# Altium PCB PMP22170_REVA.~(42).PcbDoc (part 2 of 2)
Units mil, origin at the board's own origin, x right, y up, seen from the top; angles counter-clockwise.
Board outline 4950 x 3450 mil, 2 copper layers (Top Layer, Bottom Layer), stack 62 mil thick; 76 components, 28 nets, 168 pads, 70 vias.
Unrouted connection lines stored in the file: 126.

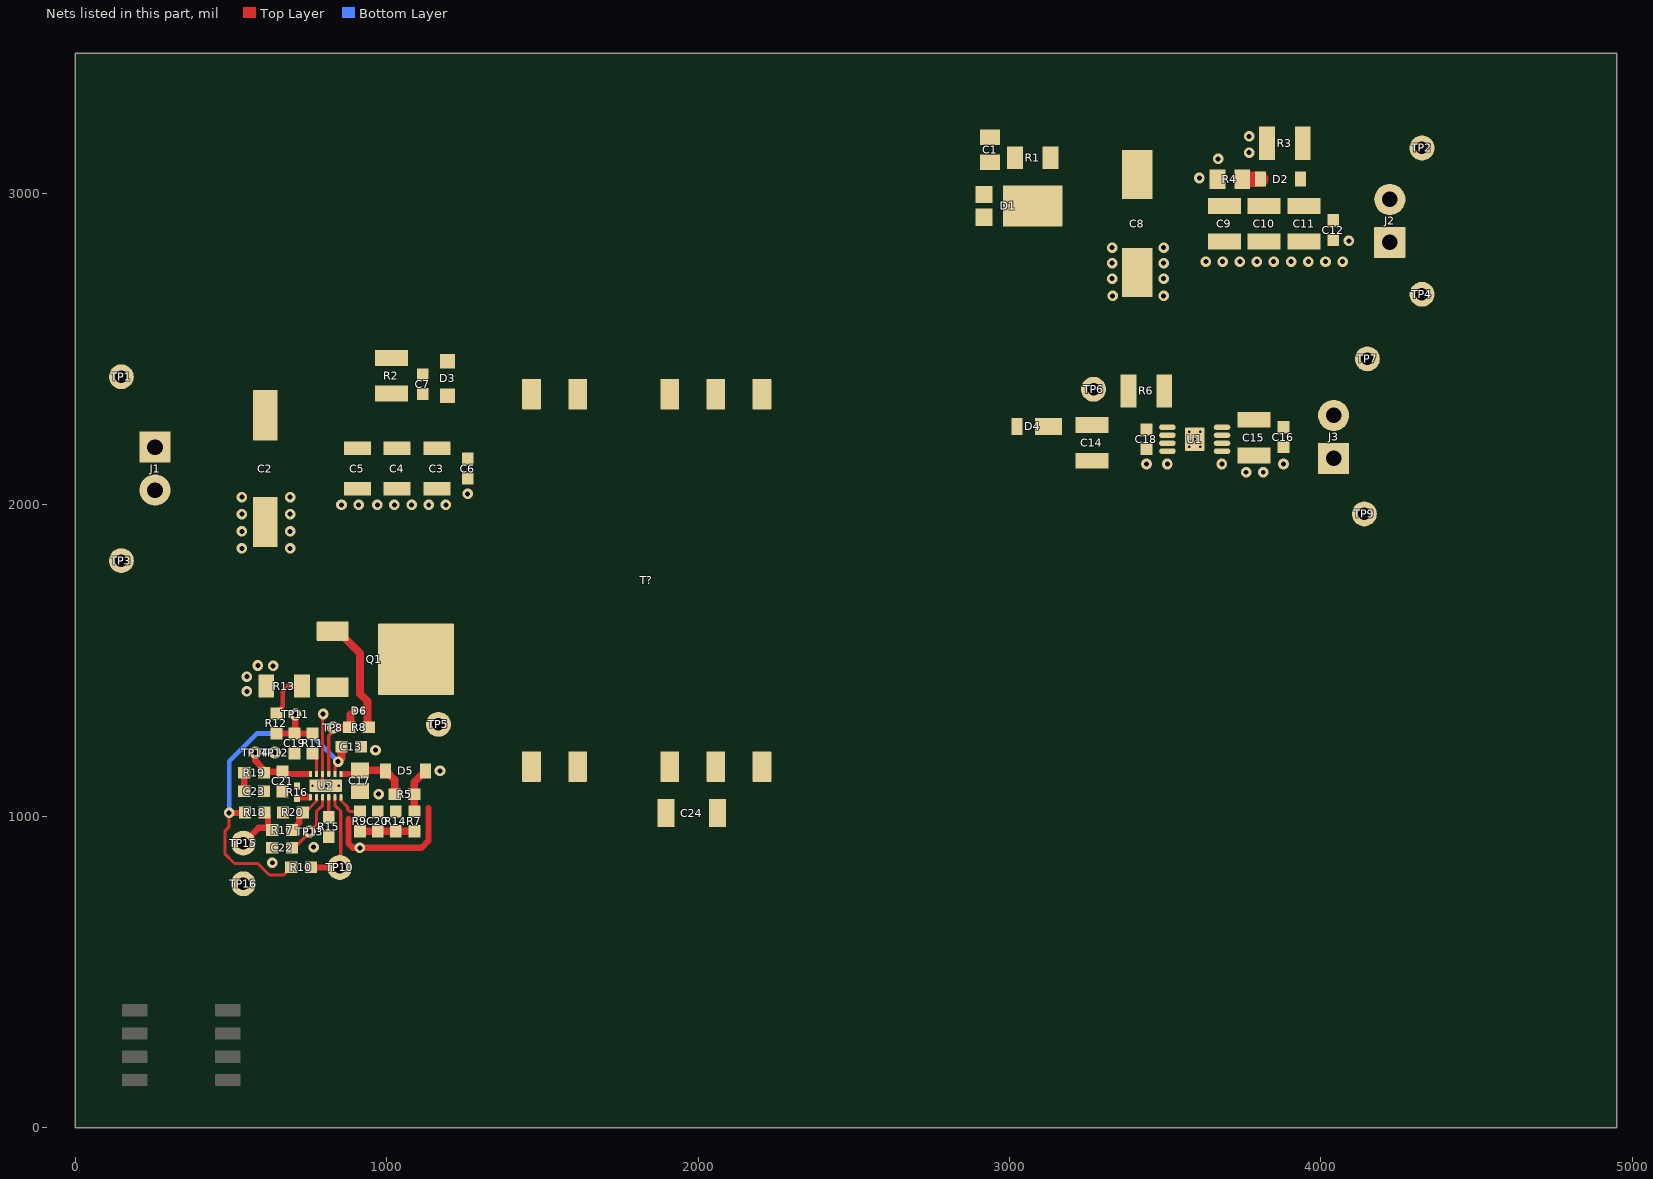
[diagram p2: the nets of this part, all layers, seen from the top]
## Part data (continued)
TP5: library part CMP-0055139-1, "Test Point, Miniature, White, TH", Color=White, Manufacturer=Keystone, Supplier Part Number 1=36-5002-ND
TP8 TP11 TP12 TP13 TP14: library part CMP-0003825-1, "1mm Test Point, SMT", Manufacturer=Any
TP15: library part CMP-0055140-1, "Test Point, Miniature, Orange, TH", Color=Orange, Manufacturer=Keystone, Supplier Part Number 1=36-5003-ND
U1: library part CMP-0013313-4, "300mA High-Voltage Ultra-Low-Iq Low-Dropout (LDO) Regulator, DGN0008D (VSSOP-8)", Alternate Manufacturer="Texas Instruments"
U2: library part CMP-0081538-1, "Automotive Grade 2.2-MHz Wide Input Non-synchronous Boost Controller, DSS0012C (WSON-12)", Alternate Manufacturer="Texas Instruments", Alternate PartNumber=LM5155QDSSRQ1

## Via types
v1: diameter 34, hole 16, Top Layer to Bottom Layer, 62 vias
v2: diameter 19.68, hole 7.87, Top Layer to Bottom Layer, 8 vias

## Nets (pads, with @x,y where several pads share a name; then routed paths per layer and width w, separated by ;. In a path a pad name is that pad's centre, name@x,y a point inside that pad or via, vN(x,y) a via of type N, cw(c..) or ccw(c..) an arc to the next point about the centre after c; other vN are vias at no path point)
GND: C2.1 C3.2 C4.2 C5.2 C6.2 C13.2 C14.2 C15.2 C16.2 C17.2 C18.2 C19.2 C20.2 C21.2 C22.2 C23.2 C24.2 J1.2 J3.1 R6.1 R13.1 R14.1 R15.1 R16.1 R20.1 T?.9 TP3.1 TP9.1 TP12.1 TP16.1 U1.3 U1.4 U1.5 U1.6 U1.7 U1.9 U2.4 U2.13@804.02,1098.17 | length 690.3
  Top Layer w10: v1(795.98,1328.19) 793.27,1325.47 793.27,1136.48 U2.4@794.17,1135.57 794.17,1108.01 v2(804.02,1098.17)
  Top Layer w20: 877.44,990.57 877.44,912.17 890.96,898.65 v1(914.02,898.65) 1112.09,898.65 1134.02,920.57 1134.02,1025.57
  other v1: 632.64,850.57 765.51,900.57 974.02,1070.57 640.98,1204.49 964.02,1212.31 550.98,1401.17 550.98,1448.19 635.04,1483.19 585.98,1484.09 535,1860 690,1860 535,1915 690,1915 535,1970 690,1970 854.76,1999.87 909.76,1999.87 969.76,1999.87 1024.76,1999.87 1080,1999.87 1135,1999.87 1189.76,1999.87 535,2025 690,2025 1260,2035 3760,2104.65 3815,2104.65 3440,2131.22 3506.93,2131.22 3682.11,2131.22 3880,2131.22
  other v2: 761.69,1098.17 846.34,1098.17 3577.28,2187.17 3612.72,2187.17 3595,2210.79 3577.28,2234.41 3612.72,2234.41
GND2: C8.2 C9.2 C10.2 C11.2 C12.2 C24.1 J2.1 R3.1 R4.1 T?.7 T?.8 TP4.1
  other v1: 3331.22,2671.22 3495,2671.22 3330,2726.22 3495,2726.22 3330,2776.22 3495,2776.22 3630.94,2781.22 3684.76,2781.22 3739.76,2781.22 3794.76,2781.22 3848.19,2781.22 3904.76,2781.22 3959.76,2781.22 4015,2781.22 4070,2781.22 3330,2826.22 3495,2826.22 4090,2847.81 3610,3049.58 3670.31,3111.22 3769.76,3131.22 3769.76,3183.7
NetC1_1: C1.1 R1.1
NetC1_2: C1.2 D1.1 D1.2 T?.5 T?.6
NetC2_2: C2.2 C3.1 C4.1 C5.1 C6.1 C7.1 D5.2 J1.1 R2.2 R5.2 R7.2 T?.11 T?.12 TP1.1 | length 145.7
  Top Layer w25: R7.2@1089.06,1015.02 1088.7,1015.38 R5.2@1088.7,1070.57 1088.7,1109.29 D5.2@1124.98,1145.57
  other v1: 1170.98,1145.57
NetC7_2: C7.2 D3.1 R2.1
NetC8_1: C8.1 C9.1 C10.1 C11.1 C12.1 D1.3 D2.1 J2.2 R1.2 R3.2 TP2.1
NetC13_1: C13.1 C14.1 C18.1 D4.1 R6.2 R10.1 R18.2 TP6.1 U1.1 U1.2 U2.2 | length 1125.5
  Top Layer w10: v1(494.02,1010.57) 494.02,966.37 480.98,953.34 480.98,878.19 510.98,848.19 585.98,848.19 622.93,811.24 669.33,811.24 R10.1@693.66,835.57 ; U2.2@833.54,1135.57 833.54,1155.63 844.02,1166.1 v1(844.02,1175.57)
  Top Layer w20: v1(494.02,1010.57) 542.97,1010.57 R18.2@544.47,1012.07
  Top Layer w25: v1(844.02,1175.57) 854.49,1186.05 C13.1@854.49,1223.19
  Bottom Layer w15: v1(494.02,1010.57) 494.02,1176.22 583.25,1265.45 754.13,1265.45 v1(844.02,1175.57)
NetC15_1: C15.1 C16.1 J3.2 TP7.1 U1.8
NetC17_1: C17.1 D5.1 R5.1 U2.1 | length 235.8
  Top Layer w10: U2.1@853.23,1135.57 859.02,1135.57
  Top Layer w20: 859.02,1135.57 902.13,1135.57 C17.1@914.06,1147.5
  Top Layer w25: C17.1@914.06,1147.5 994.11,1147.5 D5.1@996.04,1145.57 1025.71,1115.91 R5.1@1025.71,1070.57
NetC19_1: C19.1 R11.2 R12.1 TP11.1 | length 178.8
  Top Layer w20: R12.1@645.98,1266.69 647.22,1265.45 C19.1@704.02,1265.45 ; v1(706.46,1327.03) 706.46,1267.9 C19.1@704.02,1265.45 ; R11.2@761.69,1265.45 C19.1@704.02,1265.45
NetC20_1: C20.1 R7.1 R9.1 R14.2 | length 175
  Top Layer w25: R9.1@914.02,952.03 C20.1@971.02,952.03 R7.1@1089.06,952.03
NetC21_1: C21.1 R19.2 TP14.1 U2.6 | length 231
  Top Layer w10: 746.93,1135.57 U2.6@754.8,1135.57
  Top Layer w20: v1(577.66,1204.49) 577.66,1178.98 605.51,1151.12 R19.2@605.51,1139.08 609.51,1143.07 C21.1@665.51,1143.07 673.01,1135.57 746.93,1135.57
NetC22_1: C22.1 TP13.1 U2.9 | length 207.4
  Top Layer w10: C22.1@695.63,898.65 703.23,898.65 752.72,948.13 v1(752.72,950.57) 774.49,972.34 774.49,1015.77 794.17,1035.46 U2.9@794.17,1060.77
NetC23_1: C23.1 R19.1 | length 58.5
  Top Layer w20: C23.1@542.52,1080.57 R19.1@542.52,1139.08
NetD2_2: D2.2 R4.2 | length 57.9
  Top Layer w50: R4.2@3748.19,3046.22 D2.2@3806.12,3046.22
NetD3_2: D3.2 Q1.2 T?.1 T?.2 TP5.1
NetD4_2: D4.2 T?.4
NetD6_1: D6.1 R8.2 TP8.1 U2.3 | length 265.8
  Top Layer w10: U2.3@813.86,1135.57 813.86,1258.33 827.44,1271.91 v1(827.44,1284.71)
  Top Layer w15: 883.43,1327.03 D6.1@896.08,1336.39
  Top Layer w25: v1(827.44,1284.71) 878.33,1284.71 R8.2@879.49,1285.87 883.43,1289.81 883.43,1327.03
NetD6_2: D6.2 Q1.1 R8.1 | length 366
  Top Layer w25: Q1.1@826.38,1593.86 843.35,1593.86 914.06,1523.15 914.06,1393.47 938.54,1368.98 938.54,1289.81 R8.1@942.48,1285.87
NetQ1_3: Q1.3 R12.2 R13.2 | length 148.1
  Top Layer w15: R12.2@645.98,1329.69 655.98,1339.69 655.98,1342.09 665.98,1352.09 665.98,1401.17 683.01,1418.19 R13.2@727.26,1418.19
NetR9_2: R9.2 U2.12 | length 90.3
  Top Layer w10: U2.12@853.23,1060.77 853.23,1050.59 874.69,1029.14 874.69,1021.24 880.91,1015.02 R9.2@914.02,1015.02
NetR11_1: R11.1 U2.5 | length 72.2
  Top Layer w10: R11.1@761.69,1202.46 774.49,1189.67 U2.5@774.49,1135.57
NetR15_2: R15.2 U2.10 | length 63.7
  Top Layer w10: R15.2@813.86,997.07 U2.10@813.86,1060.77
NetR16_2: R16.2 U2.7 | length 43.8
  Top Layer w10: 746.94,1060.77 U2.7@754.8,1060.77
  Top Layer w20: R16.2@712.36,1057.44 715.69,1060.77 746.94,1060.77
NetR17_1: R17.1 R18.1 TP15.1 | length 169.3
  Top Layer w20: TP15.1@539.57,913.64 588.57,962.64 612.58,962.64 R17.1@619.02,969.08 ; R18.1@607.46,1012.07 619.02,1000.51 R17.1@619.02,969.08 ; R17.1@632.52,955.57 R17.1@619.02,969.08
NetR17_2: R17.2 R20.2 U2.8 | length 142.5
  Top Layer w10: R20.2@730.08,1012.07 737.92,1012.07 774.49,1048.64 U2.8@774.49,1060.77
  Top Layer w20: R17.2@695.51,955.57 719.02,979.08 719.02,1001.01 R20.2@730.08,1012.07
PG: R10.2 TP10.1 U2.11 | length 326.8
  Top Layer w10: U2.11@833.54,1060.77 833.54,1035.46 852.48,1016.52 852.48,839.04 TP10.1@849.02,835.57
  Top Layer w20: R10.2@756.65,835.57 TP10.1@849.02,835.57
pads on no net: T1.1 T1.2 T1.3 T1.4 T1.5 T1.6 T1.7 T1.8 U2.13@777.05,1098.17 U2.13@830.98,1098.17

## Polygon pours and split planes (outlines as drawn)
NetC2_2 on Top Layer "TOP_LAYER_NETC2_2_P016" (solid, remove dead copper, pour order 16): 70,2330
NetC2_2 on Top Layer "TOP_LAYER_NETC2_2_P014" (solid, remove dead copper, pour order 14): 130,2116.35 1278.52,2116.35 1278.54,2116.37 1278.54,2221.46 1250,2250 900,2250 689.54,2460.46 135.46,2460.46 100,2425 100,2145
NetQ1_3 on Top Layer "TOP_LAYER_NETQ1_3_P012" (solid, remove dead copper, pour order 12): 877.44,1461.73 870.98,1468.19 705.98,1468.19 700.98,1463.19 700.98,1374.17 706.46,1368.7 706.46,1368.19 868.65,1368.19 877.44,1376.98
NetQ1_3 on Top Layer "TOP_LAYER_NETQ1_3_P010" (solid, remove dead copper, pour order 10): 826.38,1414.33
NetC15_1 on Top Layer "TOP_LAYER_NETC15_1_P008" (solid, remove dead copper, pour order 8): 3654.04,2243.08 3654.04,2291.22 3724.04,2361.22 4149.45,2361.22 4149.45,2241.44 4126.18,2218.17 3749.9,2218.17 3731.85,2236.22 3731.54,2235.91 3661.22,2235.91
NetC13_1 on Top Layer "TOP_LAYER_NETC13_1_P006" (solid, remove dead copper, pour order 6): 3400,2251.22
NetC13_1 on Top Layer "TOP_LAYER_NETC13_1_P004" (solid, remove dead copper, pour order 4): 3420,2218.46 3536.04,2218.46 3536.04,2267.26 3527.09,2276.22 3420,2276.22
NetC8_1 on Top Layer "TOP_LAYER_NETC8_1_P002" (solid, remove dead copper, pour order 2): 3360,3141.22 3360,2891.22 4335.31,2891.22 4365,2920.91 4365,3165.83 4316.46,3214.37 3915,3214.37 3915,3111.22 3860,3056.22 3860,3008.62 3846.1,2994.72 3611.5,2994.72 3465,3141.22

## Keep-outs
Keep-Out Layer:
  text ".Layer_Name" at 577,-858.49 h60

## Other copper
Top Layer:
  text ".Layer_Name" at 577,-858.49 h60
Bottom Layer:
  text ".Layer_Name" at 577,-858.49 h60

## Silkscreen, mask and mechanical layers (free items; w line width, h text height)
Top Overlay:
  text "'.PRJ_Number'.PCB_Rev" at 3503.94,187.01 h108.27
  text ".Layer_Name" at 577,-858.49 h60
Bottom Overlay:
  text ".Layer_Name" at 577,-858.49 h60
Top Paste:
  text ".Layer_Name" at 577,-858.49 h60
Bottom Paste:
  text ".Layer_Name" at 577,-858.49 h60
Top Solder:
  text ".Layer_Name" at 577,-858.49 h60
  text ".Layer_Name" at 577,-858.49 h60
Bottom Solder:
  text ".Layer_Name" at 577,-858.49 h60
Drill Guide:
  text ".Layer_Name" at 577,-858.49 h60
M1 Board Outline:
  the board outline again, w10
  text ".Layer_Name" at 577,-858.49 h60
M2 Board Dimensions:
  rectangle: 0,-275 125,-150
  rectangle: 125,-400 500,-275
  lines w7: 0,-275 1000,-275 ; 125,-400 125,-150 ; 250,-400 250,-150 ; 500,-400 500,-150 ; 750,-400 750,-150 ; 0,-400 1000,-400 1000,-150 0,-150 0,-400
  text ".Layer_Name" at 577,-858.49 h60
M3 3D STEP Top:
  text ".Layer_Name" at 577,-858.49 h60
M4 3D STEP Bottom:
  text ".Layer_Name" at 577,-858.49 h60
M5 Assembly Top:
  lines w10: -292,-930.17 6308,-930.17 ; -292,-726.83 6310,-726.83 ; -292,-523.5 -292,-1133.5 3713,-1133.5 6310,-1133.5 6310,-523.5 -291.5,-523.5 -291.5,-1133.5 1284,-1133.5 ; 2173,-1133.5 2173,-523.5 ; 3440,-726.83 3440,-523.5 ; 4280,-726.83 4280,-523.5 ; 4902,-1140 4902,-937.17
  text "COMPONENTS MARKED 'DNP' SHOULD NOT BE POPULATED." at 1153.5,-318.5 h60
  text "ASSEMBLY VARIANT:" at 1153,-434 h60
  text ".VariantName" at 2189,-434 h60
  text "PCB VIEWED FROM TOP SIDE" at -228.5,-655.67 h60
  text "BOARD #:" at 2248,-655.67 h60
  text ".PRJ_Number" at 2793.5,-655.67 h60
  text "REV:" at 3638,-655.67 h60
  text ".PCB_Rev" at 3929.5,-655.67 h60
  text "SVN REV:" at 4476,-655.67 h60
  text ".VersionControl_RevNumber" at 4982,-655.67 h60
  text "TID #:" at 2248,-859 h60
  text ".TID" at 2793.5,-859 h60
  text "PLOT NAME =" at -228.5,-1064.34 h60
  text ".plot_File_Name" at 577,-1064.34 h60
  text "GENERATED    :" at 2250,-1064.34 h60
  text ".Print_Date" at 3119.5,-1064.34 h60
  text ".Print_Time" at 3848.5,-1064.34 h60
  text "TEXAS INSTRUMENTS" at 5113,-1064.34 h60
M6 Assembly Bottom:
  lines w10: -292.5,-727.33 6309.5,-727.33 ; -290.5,-930.67 6309.5,-930.67 ; 1115.5,-1140.5 1115.5,-937.67 ; 1737.5,-727.33 1737.5,-524 ; 2577.5,-727.33 2577.5,-524 ; 3844.5,-1134 3844.5,-524 ; 4733.5,-1134 6309,-1134 6309,-524 -292.5,-524 -292.5,-1134 2304.5,-1134 6309.5,-1134 6309.5,-524
  text "COMPONENTS MARKED 'DNP' SHOULD NOT BE POPULATED." at 6102,-318 h60
  text ".VariantName" at 5058,-434 h60
  text "ASSEMBLY VARIANT:" at 6097,-434 h60
  text ".VersionControl_RevNumber" at 1035.5,-656.17 h60
  text "SVN REV:" at 1541.5,-656.17 h60
  text ".PCB_Rev" at 2088,-656.17 h60
  text "REV:" at 2379.5,-656.17 h60
  text ".PRJ_Number" at 3224,-656.17 h60
  text "BOARD #:" at 3769.5,-656.17 h60
  text "PCB VIEWED FROM BOTTOM SIDE" at 6246,-656.17 h60
  text ".TID" at 3224,-859.5 h60
  text "TID #:" at 3769.5,-859.5 h60
  text "TEXAS INSTRUMENTS" at 904.5,-1064.84 h60
  text ".Print_Time" at 2169,-1064.84 h60
  text ".Print_Date" at 2898,-1064.84 h60
  text "GENERATED    :" at 3767.5,-1064.84 h60
  text ".plot_File_Name" at 5440.5,-1064.84 h60
  text "PLOT NAME =" at 6246,-1064.84 h60
M9 Title Sheet:
  drawing of 57 lines, arcs and shapes, not listed
  text "1" at 739.84,8036.5 h70
  text "2" at 3235.5,8036.5 h70
  text "3" at 5724.84,8036.5 h70
  text "4" at 8231.51,8036.5 h70
  text "5" at 10730.5,8036.5 h70
  text "6" at 13235.5,8036.5 h70
  text "A" at -416.5,6893.5 h70
  text "A" at 14383.5,6893.5 h70
  text "B" at -416.5,4513.5 h70
  text "B" at 14383.5,4513.5 h70
  text "C" at -416.5,2138.5 h70
  text "C" at 14383.5,2138.5 h70
  text "PROJECT TITLE:" at 11343.5,277.5 h45
  text ".PRJ_Title" at 11393.5,144.17 h70
  text "DESIGNED FOR:" at 11343.5,-23.5 h45
  text ".PRJ_Customer" at 11393.5,-163.5 h70
  text "D" at -416.5,-231.5 h70
  text "D" at 14383.5,-231.5 h70
  text "FILE NAME:" at 11343.5,-323.5 h45
  text ".PCB_File_Name_No_Path" at 11393.5,-443.5 h70
  text "Texas Instruments (TI) and/or its licensors do not warrant the accuracy or completeness of this specification" at 6374,-605.34 h45
  text "ENGINEER:" at 11343.5,-613.5 h45
  text "LAYOUT BY:" at 12848.5,-613.5 h45
  text "or any information contained therein. TI and/or its licensors do not warrant that this design will meet" at 6329.01,-718 h45
  text ".PRJ_Engineer" at 11393.5,-768.49 h70
  text ".PCB_Layout" at 12899,-768.49 h70
  text "the specifications, will be suitable for your application or fit for any particular purpose, or will operate in" at 6329.01,-830.67 h45
  text ".Layer_Name" at 577,-858.49 h60
  text "ALTIUM DESIGNER VERSION:" at 12848.5,-923.5 h45
  text "an implementation. TI and/or its licensors do not warrant that the design is production worthy. You should" at 6329.01,-943.33 h45
  text "completely validate and test your design implementation to confirm the system functionality for your application." at 6374,-1056 h45
  text ".print_Scale" at 11393.5,-1056.83 h70
  text ".Application_BuildNumber" at 12899,-1056.83 h70
  text "1" at 739.84,-1263.5 h70
  text "2" at 3235.5,-1263.5 h70
  text "3" at 5724.84,-1263.5 h70
  text "4" at 8231.51,-1263.5 h70
  text "5" at 10730.5,-1263.5 h70
  text "6" at 13235.5,-1263.5 h70
M10 Fab Notes:
  drawing of 189 lines, arcs and shapes, not listed
  text "DESIGN INFORMATION" at 12382.02,6356.17 h60
  text "MIN. TRACK WIDTH:" at 11737.46,6224.05 h60
  text "8" at 12833.7,6224.05 h60
  text "MIL" at 12988.46,6224.05 h60
  text "MIN. CLEARANCE:" at 11737.46,6099.92 h60
  text "0.2" at 12773.7,6099.93 h60
  text "mm" at 12988.46,6099.92 h60
  text "MIN. VIA PAD SIZE:" at 11737.46,5975.8 h60
  text "24" at 12803.71,5975.8 h60
  text "MIL" at 12988.46,5975.8 h60
  text "0.05mm (2MIL)" at 12432.46,5845.9 h60
  text "MINIMUM ANNULAR RING" at 11408.23,5837.67 h60
  text "EXTERNAL" at 13140.46,5837.67 h60
  text "PER" at 11608.23,5727.55 h60
  text "IPC-D-275 CLASS 2 LEVEL C" at 11828.23,5727.54 h60
  text "MIL, HOLES" at 13316.46,5627.07 h60
  text "+/-" at 12924,5618.48 h60
  text "+/-" at 13778,5618.48 h60
  text "REGISTRATION TOLERANCES:" at 11408.23,5617.42 h60
  text "METAL" at 12608,5617.42 h60
  text "5" at 13184.2,5617.42 h60
  text "3" at 14017.2,5617.42 h60
  text "MIL" at 14133.46,5617.42 h60
  text "HOLE SIZE TOLERANCE (UNLESS OTHERWISE SPECIFIED):" at 11408.23,5519.1 h60
  text "+/-" at 13778,5516.23 h60
  text "3" at 14017.2,5515.17 h60
  text "MIL" at 14133.46,5515.17 h60
  text "MATERIAL:" at 11333.46,5377.52 h60
  text "FR-4 High Tg" at 12319.9,5249 h60
  text "X" at 12175.46,5241.01 h60
  text "FR-408" at 11754.46,5236.49 h60
  text "OTHER" at 13242.46,5236.49 h60
  text "62 MIL (1.6mm) +/-10%" at 12074.56,5093.46 h60
  text "X" at 11954.46,5091.01 h60
  text "THICKNESS:" at 11408.23,5085.24 h60
  text "OTHER" at 13359.46,5085.24 h60
  text "TOLERANCE:" at 11408.23,4946.92 h60
  text "X" at 12256.46,4946.92 h60
  text "ANSI IPC-6012 TYPE 3 CLASS 2" at 12434.48,4946.92 h60
  text "OTHER +/-" at 12434.46,4802.73 h60
  text "BOW & TWIST:" at 11408.23,4657.54 h60
  text "X" at 12256.46,4657.54 h60
  text "ANSI IPC-6012 TYPE 3 CLASS 2" at 12434.48,4657.54 h60
  text "OTHER +/-" at 12434.46,4510.85 h60
  text "DRILLING:" at 11333.46,4380.23 h60
  text "NC_DRILL FILES" at 13094.46,4275.04 h60
  text "REFERENCE:" at 11408.23,4271.1 h60
  text "X" at 12065.46,4271.01 h60
  text "AS SHOWN" at 12243.46,4271.1 h60
  text "X" at 12966.46,4271.1 h60
  text "OTHER" at 13392.46,4128.85 h60
  text "PTH COPPER THICKNESS:" at 11407.91,4125.32 h60
  text "X" at 12547.14,4125.32 h60
  text "20-30 um" at 12675.14,4125.32 h60
  text "BOARD FINISH:" at 11333.46,3977.73 h60
  text "SILKSCREEN:" at 11488.68,3867.6 h60
  text "X" at 12446.46,3867.6 h60
  text "TOP" at 12563.46,3867.6 h60
  text "X" at 12956.46,3867.6 h60
  text "BOTTOM" at 13074.46,3867.6 h60
  text "SILKSCREEN COLOR:" at 11488.68,3712.41 h60
  text "X" at 12445.46,3712.41 h60
  text "WHITE" at 12563.46,3712.41 h60
  text "OTHER" at 13074.46,3712.41 h60
  text "X" at 12576.46,3568.96 h60
  text "GREEN" at 12694.46,3568.96 h60
  text "OTHER" at 13312.46,3568.96 h60
  text "SOLDER RESIST COLOR:" at 11488.68,3562.1 h60
  text "X" at 12576.46,3414.71 h60
  text "MATTE" at 12694.46,3414.71 h60
  text "SEMI-GLOSS" at 13312,3414.07 h60
  text "IMMERSION GOLD (ENIG)" at 12394.46,3241.94 h60
  text "ENEPIG" at 13732,3234.72 h60
  text "SURFACE FINISH:" at 11333.46,3233.72 h60
  text "X" at 12216.46,3233.72 h60
  text "IMM. TIN/SILVER OR EQUIV" at 11663,3096.4 h60
  text "OTHER" at 13094.46,3092.47 h60
  text "ARRAY/PANEL:" at 11333.46,2937.09 h60
  text "CUT AND TRIM PER M1 BOARD OUTLINE" at 12394.46,2928.87 h60
  text "N.C. ROUTE" at 12394.46,2792.9 h60
  text "X" at 13082.46,2792.9 h60
  text "V. SCORE" at 13260.46,2792.9 h60
  text "CERTIFICATION:" at 11333.46,2663.77 h60
  text "MATERIALS AND WORKMANSHIP FOR ALL PCBS" at 12058.46,2663.77 h60
  text "TO MEET OR EXCEED THE REQUIREMENTS OF:" at 12058.46,2569.71 h60
  text "X" at 11695.97,2441.08 h60
  text "ANSI IPC-A-600F CLASS ->" at 11823.96,2441.08 h60
  text "X" at 13471.97,2441.08 h60
  text "2" at 13581.96,2441.08 h60
  text "1" at 13266.96,2439.58 h60
  text "3" at 13935.96,2439.58 h60
  text "X" at 12507.97,2293.39 h60
  text "RoHS" at 12635.96,2293.39 h60
  text "OTHER" at 13280.36,2293.39 h60
  text "PER ORDER" at 13677.42,2293.39 h60
  text "ALL BOARDS MUST MEET OR EXCEED UL94-V0 REQUIREMENTS." at 11361,2139.57 h60
  text "PCB MUST BEAR THE UL94V-0 UL REGISTERED MATERIAL ID NUMBER" at 11361,2023.5 h60
  text "ADDITIONAL REQUIREMENTS:" at 11333.46,1854.08 h60
  text "MICROSECTION:" at 11408.23,1746.95 h60
  text "YES" at 12313.96,1746.95 h60
  text "REQUIRED" at 13175.46,1602.62 h60
  text "BARE BOARD ELEC. TEST:" at 11408.23,1599.76 h60
  text "NONE" at 12713.96,1599.76 h60
  text "X" at 13057.46,1599.76 h60
  text "PER ORDER" at 13767.46,1599.76 h60
  text "XX MIL VIAS REQUIRE NON-CONDUCTIVE FILL AND PLANARIZE" at 11576.38,1394.82 h59
  text "XX MIL VIAS REQUIRE CONDUCTIVE FILL AND PLANARIZE" at 11584.38,1290.84 h60
  text "OUTER XX MIL TRACES REQUIRE 50 OHM SINGLE-ENDED IMPEDANCE" at 11583.39,1127.46 h58
  text "LAYER 2 & 3 (INNER LAYERS) XX MIL WIDE, XX MIL SPACE / TRACES REQUIRE 100 OHM DIFFERENTIAL IMPEDANCE" at 11575.39,891.74 h60
  text ".Layer_Name" at 577,-858.49 h60
M11 Gerber Information:
  lines w10: -292,-930.17 6308,-930.17 ; -292,-726.83 6310,-726.83 ; -292,-523.5 -292,-1133.5 3713,-1133.5 6310,-1133.5 6310,-523.5 -291.5,-523.5 -291.5,-1133.5 1284,-1133.5 ; 2173,-1133.5 2173,-523.5 ; 3440,-726.83 3440,-523.5 ; 4280,-726.83 4280,-523.5 ; 4902,-1140 4902,-937.17
  text "ALL ARTWORK VIEWED FROM TOP SIDE" at -228.5,-655.67 h60
  text "BOARD #:" at 2248,-655.67 h60
  text ".PRJ_Number" at 2793.5,-655.67 h60
  text "REV:" at 3638,-655.67 h60
  text ".PCB_Rev" at 3929.5,-655.67 h60
  text "SVN REV:" at 4476,-655.67 h60
  text ".VersionControl_RevNumber" at 4982,-655.67 h60
  text "LAYER NAME =" at -228.5,-858.49 h60
  text "TID #:" at 2248,-859 h60
  text ".TID" at 2793.5,-859 h60
  text "PLOT NAME =" at -228.5,-1064.34 h60
  text ".plot_File_Name" at 577,-1064.34 h60
  text "GENERATED    :" at 2250,-1064.34 h60
  text ".Print_Date" at 3119.5,-1064.34 h60
  text ".Print_Time" at 3848.5,-1064.34 h60
  text "TEXAS INSTRUMENTS" at 5113,-1064.34 h60
M12 Stackup:
  drawing of 191 lines, arcs and shapes, not listed
  text "Layer" at 9811.59,7784.94 h60
  text "Name" at 10221.51,7784.94 h60
  text "Material" at 11151.25,7784.94 h60
  text "Thickness" at 12011.02,7784.94 h60
  text "Constant" at 12660.85,7784.94 h60
  text "Board Layer Stack" at 13230.71,7784.94 h60
  text "1" at 9811.59,7664.94 h60
  text "Top Overlay" at 10221.51,7664.94 h60
  text "2" at 9811.59,7544.94 h60
  text "Top Solder" at 10221.51,7544.94 h60
  text "Solder Resist" at 11151.25,7544.94 h60
  text "0.40mil" at 12011.02,7544.94 h60
  text "3.5" at 12660.85,7544.94 h60
  text "3" at 9811.59,7424.94 h60
  text "Top Layer" at 10221.51,7424.94 h60
  text "Copper" at 11151.25,7424.94 h60
  text "1.40mil" at 12011.02,7424.94 h60
  text "4" at 9811.59,7304.94 h60
  text "Dielectric1" at 10221.51,7304.94 h60
  text "FR-4" at 11151.25,7304.94 h60
  text "59.20mil" at 12011.02,7304.94 h60
  text "4.8" at 12660.85,7304.94 h60
  text "5" at 9811.59,7184.94 h60
  text "Bottom Layer" at 10221.51,7184.94 h60
  text "Copper" at 11151.25,7184.94 h60
  text "1.40mil" at 12011.02,7184.94 h60
  text "6" at 9811.59,7064.94 h60
  text "Bottom Solder" at 10221.51,7064.94 h60
  text "Solder Resist" at 11151.25,7064.94 h60
  text "0.40mil" at 12011.02,7064.94 h60
  text "3.5" at 12660.85,7064.94 h60
  text "7" at 9811.59,6944.94 h60
  text "Bottom Overlay" at 10221.51,6944.94 h60
  text ".Layer_Name" at 577,-858.49 h60
M13 Component Bodies Top:
  text ".Layer_Name" at 577,-858.49 h60
M14 Component Bodies Bottom:
  text ".Layer_Name" at 577,-858.49 h60
M15 Courtyards Top:
  text ".Layer_Name" at 577,-858.49 h60
M16 Courtyards Bottom:
  text ".Layer_Name" at 577,-858.49 h60
Drill Drawing:
  circle w10: c5363.72,3195.96 r27.63
  lines w10: 5336.09,2974.95 5391.34,2974.95 5363.72,2919.7 5336.09,2974.95 ; 5336.09,3044.02 5391.34,3044.02 5391.34,3099.27 5336.09,3099.27 5336.09,3044.02 ; 5336.09,3306.47 5349.9,3306.47 5363.72,3292.66 5377.53,3306.47 5391.34,3306.47 5377.53,3320.28 5391.34,3334.1 5377.53,3334.1 5363.72,3347.91 5349.9,3334.1 5336.09,3334.1 5349.9,3320.28 5336.09,3306.47
  lines w12: 5286,2882.4 8517.49,2882.4 ; 5286,3379.68 8517.49,3379.68 ; 5623.86,2758.08 5623.86,3504 ; 5955.86,2758.08 5955.86,3504 ; 6592.43,2758.08 6592.43,3504 ; 6851.57,2758.08 6851.57,3504 ; 7226.72,2758.08 7226.72,3504 ; 7951.05,2758.08 7951.05,3504 ; 5286,2758.08 8517.49,2758.08 8517.49,3504 5286,3504 5286,2758.08
  text "Symbol" at 5360.59,3416.98 h72
  text "Quantity" at 5661.16,3416.98 h72
  text "Finished Hole Size" at 5993.16,3416.98 h72
  text "Plated" at 6629.72,3416.98 h72
  text "Hole Type" at 6888.86,3416.98 h72
  text "Drill Layer Pair" at 7264.02,3416.98 h72
  text "Hole Tolerance" at 7988.35,3416.98 h72
  text "8" at 5661.16,3292.66 h60
  text "7.87mil (0.200mm)" at 5993.16,3292.66 h60
  text "PTH" at 6629.72,3292.66 h60
  text "Round" at 6888.86,3292.66 h60
  text "Top Layer - Bottom Layer" at 7264.02,3292.66 h60
  text "62" at 5661.16,3168.34 h60
  text "16.00mil (0.406mm)" at 5993.16,3168.34 h60
  text "PTH" at 6629.72,3168.34 h60
  text "Round" at 6888.86,3168.34 h60
  text "Top Layer - Bottom Layer" at 7264.02,3168.34 h60
  text "11" at 5661.16,3044.02 h60
  text "40.00mil (1.016mm)" at 5993.16,3044.02 h60
  text "PTH" at 6629.72,3044.02 h60
  text "Round" at 6888.86,3044.02 h60
  text "Top Layer - Bottom Layer" at 7264.02,3044.02 h60
  text "6" at 5661.16,2919.7 h60
  text "50.00mil (1.270mm)" at 5993.16,2919.7 h60
  text "PTH" at 6629.72,2919.7 h60
  text "Round" at 6888.86,2919.7 h60
  text "Top Layer - Bottom Layer" at 7264.02,2919.7 h60
  text "87 Total" at 5661.16,2795.38 h60
  text ".Layer_Name" at 577,-858.49 h60
M17 Embedded Cavity:
  text ".Layer_Name" at 577,-858.49 h60
M18 Embedded Assembly:
  text ".Layer_Name" at 577,-858.49 h60
M19 Embedded Keepout:
  text ".Layer_Name" at 577,-858.49 h60

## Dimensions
0,-400 to 1000,-400 on M2 Board Dimensions
0,0 to 0,3450 on M2 Board Dimensions
0,0 to 4950,0 on M2 Board Dimensions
